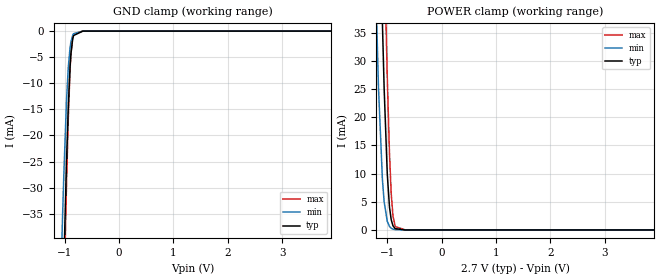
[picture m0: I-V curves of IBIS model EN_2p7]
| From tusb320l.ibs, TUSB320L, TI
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|   Model
[Model]   EN_2p7
Model_type   Input
Vinl = 0.81
Vinh = 1.89
|   typ   min   max
C_comp   0.453pF   0.401pF   0.510pF
[Voltage Range]   2.7   2.699   2.701
[Temperature Range]   27   105   -40
[Power Clamp Reference]   2.7   2.699   2.701
[GND Clamp Reference]   0   0   0
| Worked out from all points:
|   GND clamp passes 1 mA (typ) near -0.84 V on its own axis
|   POWER clamp passes 1 mA (typ) near -0.90 V on its own axis
[GND Clamp]
|   Voltage   I(typ)   I(min)   I(max)
-2.7V     -962.9mA   -896.1mA   -1.01A
-1.056V   -62.35mA   -41.87mA   -71.32mA
-1.04V    -54.95mA   -35.76mA   -63.2mA
-1.015V   -44.25mA   -27.23mA   -51.34mA
-966.6mV  -24.94mA   -13.3mA    -29.32mA
-934.2mV  -14.47mA   -6.987mA   -16.81mA
-901.8mV  -6.901mA   -3.195mA   -7.415mA
-885.6mV  -4.378mA   -2.071mA   -4.308mA
-853.2mV  -1.522mA   -823.8uA   -1.129mA
-837mV    -853uA     -511.2uA   -532.7uA
-666.9mV  -4.276uA   -5.499uA   -3.78uA
5.4V      0A         0A         0A
[POWER Clamp]
|   Voltage   I(typ)   I(min)   I(max)
-2.7V     943.9mA    860.1mA    1.001A
-1.242V   107.3mA    54.31mA    147.1mA
-1.161V   67.86mA    25.44mA    103.6mA
-1.088V   36.66mA    8.96mA     66.56mA
-1.056V   25.04mA    4.964mA    51.18mA
-999mV    9.991mA    1.543mA    27.12mA
-958.5mV  4.109mA    631.7uA    13.69mA
-926.1mV  1.801mA    304.8uA    6.412mA
-893.7mV  743.7uA    146.3uA    2.451mA
-853.2mV  237.1uA    58.39uA    609.7uA
-666.9mV  1.676uA    1.31uA     1.325uA
5.4V      0A         0A         0A
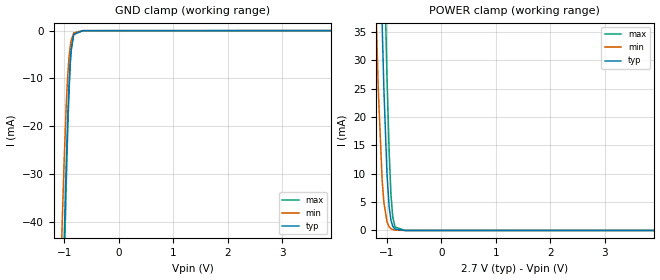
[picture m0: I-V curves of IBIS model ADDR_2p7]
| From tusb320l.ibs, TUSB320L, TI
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|   Model
[Model]   ADDR_2p7
Model_type   Input
Vinl = 0.81
Vinh = 1.89
|   typ   min   max
C_comp   0.490pF   0.431pF   0.550pF
[Voltage Range]   2.7   2.699   2.701
[Temperature Range]   27   105   -40
[Power Clamp Reference]   2.7   2.699   2.701
[GND Clamp Reference]   0   0   0
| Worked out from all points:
|   GND clamp passes 1 mA (typ) near -0.83 V on its own axis
|   POWER clamp passes 1 mA (typ) near -0.90 V on its own axis
[GND Clamp]
|   Voltage   I(typ)   I(min)   I(max)
-2.7V     -997.9mA   -935.7mA   -1.04A
-1.056V   -67.17mA   -46.41mA   -75.63mA
-1.04V    -59.46mA   -39.93mA   -67.25mA
-1.007V   -44.69mA   -27.98mA   -51mA
-966.6mV  -27.95mA   -15.63mA   -32.12mA
-942.3mV  -19.28mA   -10.02mA   -22.02mA
-918mV    -12.08mA   -5.935mA   -13.39mA
-893.7mV  -6.726mA   -3.267mA   -6.864mA
-877.5mV  -4.245mA   -2.127mA   -3.929mA
-828.9mV  -837.9uA   -548.3uA   -510.3uA
-658.8mV  -14.38uA   -23.37uA   -23.64uA
5.4V      0A         0A         0A
[POWER Clamp]
|   Voltage   I(typ)   I(min)   I(max)
-2.7V     943.9mA    860.1mA    1.001A
-1.242V   107.3mA    54.31mA    147.1mA
-1.161V   67.86mA    25.44mA    103.6mA
-1.088V   36.66mA    8.964mA    66.56mA
-1.056V   25.04mA    4.969mA    51.18mA
-999mV    9.996mA    1.548mA    27.12mA
-958.5mV  4.115mA    637.2uA    13.7mA
-926.1mV  1.807mA    310.2uA    6.418mA
-893.7mV  749.7uA    151.7uA    2.458mA
-853.2mV  243.2uA    63.79uA    616.9uA
-666.9mV  7.475uA    6.435uA    8.422uA
5.4V      0A         0A         0A
